VERSION 5.8 ;

UNITS
  DATABASE MICRONS 4000 ;
END UNITS

MANUFACTURINGGRID 0.00025 ;


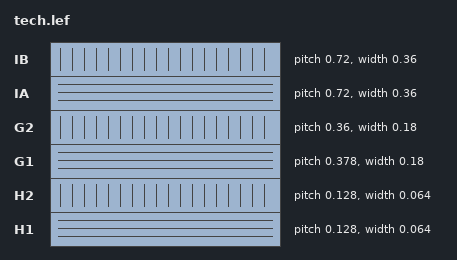
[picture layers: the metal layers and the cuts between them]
LAYER H1
  TYPE ROUTING ;
  DIRECTION HORIZONTAL ;
  PITCH 0.128 0.128 ;
  OFFSET 0.000 0.000 ;
  # Hx.W.1
  WIDTH 0.064 ;
  MINWIDTH 0.064 ;
  # Hx.W.2
  MAXWIDTH 4.000 ;
  # Hx.A.1
  AREA 0.020 ;
  # Hx.A.2
  MINENCLOSEDAREA 0.070 ;
  # Hx.SE.1
  MINSTEP 0.06425 MAXEDGES 1 ;
END H1

LAYER H2
  TYPE ROUTING ;
  DIRECTION VERTICAL ;
  PITCH 0.128 0.128 ;
  OFFSET 0.000 0.000 ;
  # Hx.W.1
  WIDTH 0.064 ;
  MINWIDTH 0.064 ;
  # Hx.W.2
  MAXWIDTH 4.000 ;
  # Hx.A.1
  AREA 0.020 ;
  # Hx.A.2
  MINENCLOSEDAREA 0.070 ;
  # Hx.SE.1
  MINSTEP 0.06425 MAXEDGES 1 ;

END H2

LAYER G1
  TYPE ROUTING ;
  DIRECTION HORIZONTAL ;
  PITCH 0.378 0.378 ;
  OFFSET 0.000 0.000 ;
  # Gx.W.1
  WIDTH 0.180 ;
  MINWIDTH 0.180 ;
  # Gx.W.2
  MAXWIDTH 10.80 ;
  # Gx.A.1
  AREA 0.1080 ;
  # Gx.A.2
  MINENCLOSEDAREA 0.3303 ;
  # Gx.SE.1
  MINSTEP 0.18025 MAXEDGES 1 ;
END G1

LAYER G2
  TYPE ROUTING ;
  DIRECTION VERTICAL ;
  PITCH 0.360 0.360 ;
  OFFSET 0.000 0.000 ;
  # Gx.W.1
  WIDTH 0.180 ;
  MINWIDTH 0.180 ;
  # Gx.W.2
  MAXWIDTH 10.80 ;
  # Gx.A.1
  AREA 0.1080 ;
  # Gx.A.2
  MINENCLOSEDAREA 0.3303 ;
  # Gx.SE.1
  MINSTEP 0.18025 MAXEDGES 1 ;
END G2

LAYER IA
  TYPE ROUTING ;
  DIRECTION HORIZONTAL ;
  PITCH 0.720 0.720 ;
  OFFSET 0.360 0.360 ;
  WIDTH 0.360 ;
  # Iz.W.1
  MINWIDTH 0.360 ;
  # Iz.W.2
  MAXWIDTH 10.800 ;
  # Iz.A.1
  AREA 0.3888 ;
  # Iz.A.2
  MINENCLOSEDAREA 0.7047 ;
END IA

LAYER IB
  TYPE ROUTING ;
  DIRECTION VERTICAL ;
  PITCH 0.720 0.720 ;
  OFFSET 0.360 0.360 ;
  WIDTH 0.360 ;
  # Iz.W.1
  MINWIDTH 0.360 ;
  # Iz.W.2
  MAXWIDTH 10.800 ;
  # Iz.A.1
  AREA 0.3888 ;
  # Iz.A.2
  MINENCLOSEDAREA 0.7047 ;
END IB

END LIBRARY
